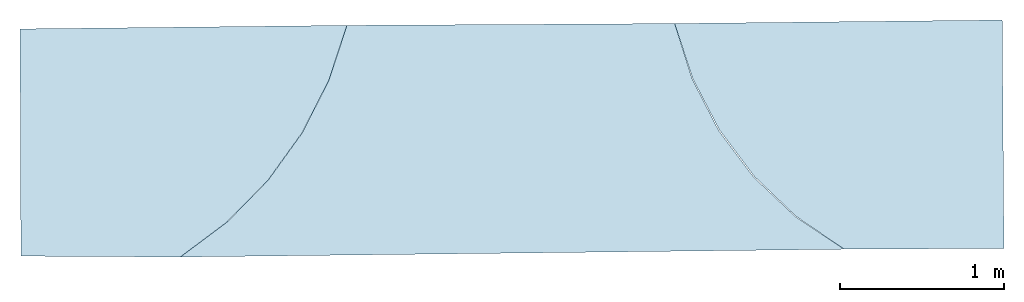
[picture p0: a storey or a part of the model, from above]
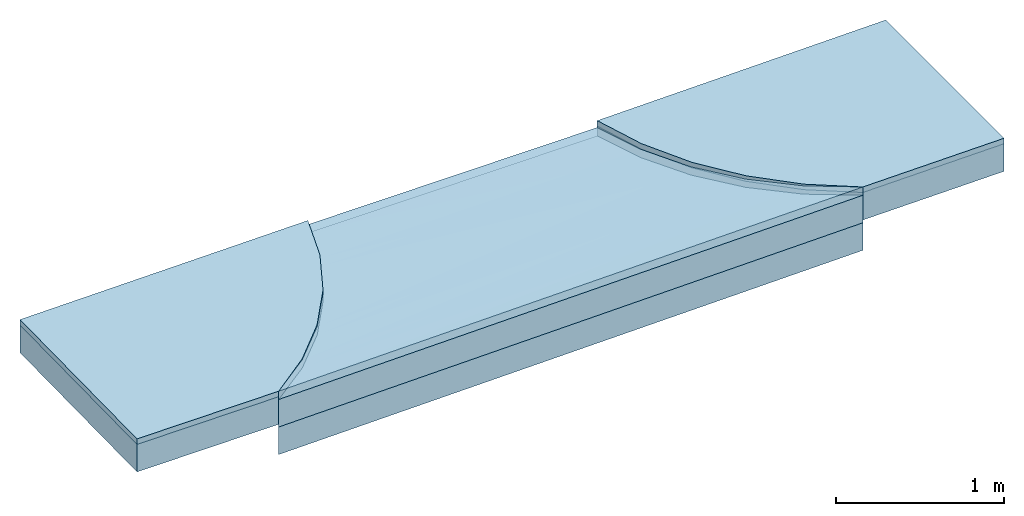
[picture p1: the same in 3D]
Properties of the parts of a building model (IFC2X3)

# File
Description: ViewDefinition [CoordinationView]
File name: Plan EP2
Time: 2022-11-14T13:14:50
Made in: IfcPlusPlus

# IfcSite: Surface terrain (2)
PSET-MENSURA - Surface Horizontale: 0 m2; Surface Selon la pente: 0 m2; Valeur décapage par défaut: 0 m
IfcElementQuantity - Surface Horizontale: 0 m2; Surface Selon la pente: 0 m2; Valeur décapage par défaut: 0 m
Group: Surfaces 3D
Name | Description | Nom Surface MNT
Terrain | Surface 3D : Terrain | Terrain
Terrain - Surface Projet | Surface 3D : Terrain - Surface Projet | Terrain - Surface Projet

# IfcBuildingElementProxy: Surface projet (3)
In: Extérieur (Terrain)
PSET-MENSURA - Volume Déblais: Pas calculé; Volume Remblais: Pas calculé
Group: Surfaces 3D
Name | Description | Numéro de PTF | Code de PTF | PSET-MENSURA, Surface Horizontale (m2) = IfcElementQuantity, Surface Horizontale (m2) | PSET-MENSURA, Surface Selon la pente (m2) = IfcElementQuantity, Surface Selon la pente (m2) | PSET-MENSURA, Epaisseur Décaissement (m) = IfcElementQuantity, Epaisseur Décaissement (m) | PSET-MENSURA, Epaisseur < Tout venant 0/31.5 > (m) = IfcElementQuantity, Epaisseur < Tout venant 0/31.5 > (m) | PSET-MENSURA, Volume < Tout venant 0/31.5 > (m3) = IfcElementQuantity, Volume < Tout venant 0/31.5 > (m3)
1 | Nouveau Code 2 : 1(Surface Projet) | 1 | Nouveau Code 2 | 2.24801 | 2.24847 | 0.24 | 0.2 | 0.449693 | PSET-MENSURA - Epaisseur < Pavé béton >: 0.04 m; Volume < Pavé béton >: 0.0899386 m3; IfcElementQuantity - Epaisseur < Pavé béton >: 0.04 m; Volume < Pavé béton >: 0.0899386 m3
3 | Voirie légère : 3(Surface Projet) | 3 | Voirie légère | 3.80548 | 3.80617 | 0.46 | PSET-MENSURA - Epaisseur < Enrobés >: 0.06 m; Volume < Enrobés >: 0.22837 m3; Epaisseur < GB 0/14 >: 0.2 m; Volume < GB 0/14 >: 0.761234 m3; Epaisseur < GNT 0/31.5 >: 0.2 m; Volume < GNT 0/31.5 >: 0.761234 m3; IfcElementQuantity - Epaisseur < Enrobés >: 0.06 m; Volume < Enrobés >: 0.22837 m3; Epaisseur < GB 0/14 >: 0.2 m; Volume < GB 0/14 >: 0.761234 m3; Epaisseur < GNT 0/31.5 >: 0.2 m; Volume < GNT 0/31.5 >: 0.761234 m3
2 | Nouveau Code 1 : 2(Surface Projet) | 2 | Nouveau Code 1 | 2.25277 | 2.25308 | 0.24 | 0.2 | 0.450616 | PSET-MENSURA - Epaisseur < Dallage béton >: 0.04 m; Volume < Dallage béton >: 0.0901233 m3; IfcElementQuantity - Epaisseur < Dallage béton >: 0.04 m; Volume < Dallage béton >: 0.0901233 m3

# IfcGroup (11)
Name | Group
Terrains
Terrain | Terrains
Surfaces 3D | Terrain
Surfaces projet
Surface Projet | Surfaces projet
Couches Structure PTF | Surface Projet
Couches structures | Couches Structure PTF
Surfaces 3D | Surface Projet
Surfaces 3D | Couches Structure PTF
Terrain - Surface Projet | Terrains
Surfaces 3D | Terrain - Surface Projet

# IfcSlab: Structure de surface projet (7)
In: Extérieur (Terrain)
Group: Couches structures
Name | Description | Material = Nom couche | PSET-MENSURA, Epaisseur couche (m) = IfcElementQuantity, Epaisseur couche (m) | PSET-MENSURA, Surface Horizontale (m2) = IfcElementQuantity, Surface Horizontale (m2) | PSET-MENSURA, Surface Selon la pente (m2) = IfcElementQuantity, Surface Selon la pente (m2) | PSET-MENSURA, Volume couche (m3) = IfcElementQuantity, Volume couche (m3)
Pavé béton | Nouveau Code 2(Surface Projet) / Pavé béton : 0.04m | Pavé béton | 0.04 | 2.24801 | 2.24847 | 0.0899386
Tout venant 0/31.5 | Nouveau Code 2(Surface Projet) / Tout venant 0/31.5 : 0.2m | Tout venant 0/31.5 | 0.2 | 2.24801 | 2.24847 | 0.449693
Enrobés | Voirie légère(Surface Projet) / Enrobés : 0.06m | Enrobés | 0.06 | 3.80548 | 3.80617 | 0.22837
GB 0/14 | Voirie légère(Surface Projet) / GB 0/14 : 0.2m | GB 0/14 | 0.2 | 3.80548 | 3.80617 | 0.761234
GNT 0/31.5 | Voirie légère(Surface Projet) / GNT 0/31.5 : 0.2m | GNT 0/31.5 | 0.2 | 3.80548 | 3.80617 | 0.761234
Dallage béton | Nouveau Code 1(Surface Projet) / Dallage béton : 0.04m | Dallage béton | 0.04 | 2.25277 | 2.25308 | 0.0901233
Tout venant 0/31.5 | Nouveau Code 1(Surface Projet) / Tout venant 0/31.5 : 0.2m | Tout venant 0/31.5 | 0.2 | 2.25277 | 2.25308 | 0.450616

# IfcSlab: Surface projet (3)
In: Extérieur (Terrain)
PSET-MENSURA - Volume Déblais: Pas calculé; Volume Remblais: Pas calculé
Group: Surfaces 3D
Name | Description | Material | Numéro de PTF | Code de PTF | PSET-MENSURA, Surface Horizontale (m2) = IfcElementQuantity, Surface Horizontale (m2) | PSET-MENSURA, Surface Selon la pente (m2) = IfcElementQuantity, Surface Selon la pente (m2) | PSET-MENSURA, Epaisseur Décaissement (m) = IfcElementQuantity, Epaisseur Décaissement (m) | PSET-MENSURA, Epaisseur < Tout venant 0/31.5 > (m) = IfcElementQuantity, Epaisseur < Tout venant 0/31.5 > (m) | PSET-MENSURA, Volume < Tout venant 0/31.5 > (m3) = IfcElementQuantity, Volume < Tout venant 0/31.5 > (m3)
1 | Nouveau Code 2 : 1(Surface Projet) | Pavé béton 0.04 m, Tout venant 0/31.5 0.2 m | 1 | Nouveau Code 2 | 2.24801 | 2.24847 | 0.24 | 0.2 | 0.449693 | PSET-MENSURA - Epaisseur < Pavé béton >: 0.04 m; Volume < Pavé béton >: 0.0899386 m3; IfcElementQuantity - Epaisseur < Pavé béton >: 0.04 m; Volume < Pavé béton >: 0.0899386 m3
3 | Voirie légère : 3(Surface Projet) | Enrobés 0.06 m, GB 0/14 0.2 m, GNT 0/31.5 0.2 m | 3 | Voirie légère | 3.80548 | 3.80617 | 0.46 | PSET-MENSURA - Epaisseur < Enrobés >: 0.06 m; Volume < Enrobés >: 0.22837 m3; Epaisseur < GB 0/14 >: 0.2 m; Volume < GB 0/14 >: 0.761234 m3; Epaisseur < GNT 0/31.5 >: 0.2 m; Volume < GNT 0/31.5 >: 0.761234 m3; IfcElementQuantity - Epaisseur < Enrobés >: 0.06 m; Volume < Enrobés >: 0.22837 m3; Epaisseur < GB 0/14 >: 0.2 m; Volume < GB 0/14 >: 0.761234 m3; Epaisseur < GNT 0/31.5 >: 0.2 m; Volume < GNT 0/31.5 >: 0.761234 m3
2 | Nouveau Code 1 : 2(Surface Projet) | Dallage béton 0.04 m, Tout venant 0/31.5 0.2 m | 2 | Nouveau Code 1 | 2.25277 | 2.25308 | 0.24 | 0.2 | 0.450616 | PSET-MENSURA - Epaisseur < Dallage béton >: 0.04 m; Volume < Dallage béton >: 0.0901233 m3; IfcElementQuantity - Epaisseur < Dallage béton >: 0.04 m; Volume < Dallage béton >: 0.0901233 m3
